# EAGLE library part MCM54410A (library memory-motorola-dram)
MEMORY

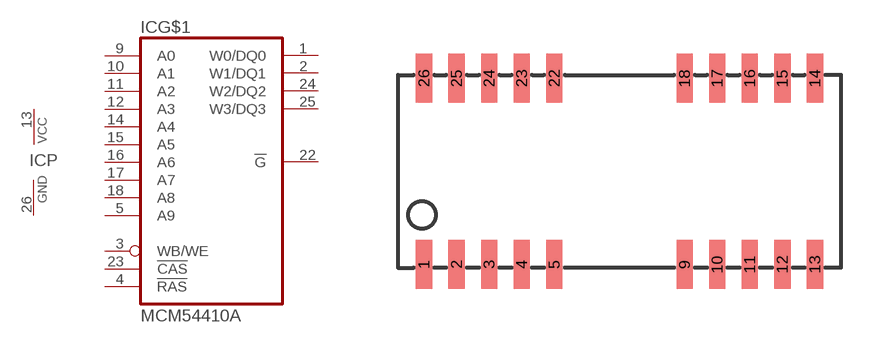
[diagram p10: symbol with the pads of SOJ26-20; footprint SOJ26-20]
Designator prefix IC; gates G$1=CM54410A P=PWRN

## MCM54410A (OC_FARNELL: unknown; OC_NEWARK: unknown)  [SOJ26-20]
1  G$1:W0/DQ0
2  G$1:W1/DQ1
3  G$1:WB/WE  in
4  G$1:!RAS  in
5  G$1:A9  in
9  G$1:A0  in
10  G$1:A1  in
11  G$1:A2  in
12  G$1:A3  in
13  P:VCC  pwr
14  G$1:A4  in
15  G$1:A5  in
16  G$1:A6  in
17  G$1:A7  in
18  G$1:A8  in
22  G$1:!G  in
23  G$1:!CAS  in
24  G$1:W2/DQ2
25  G$1:W3/DQ3
26  P:GND  pwr

## Footprint SOJ26-20 (pad centres in mm)
Small Outline J-Bend
smd 0.635 x 1.905: 1 -7.62,-3.632; 2 -6.35,-3.632; 3 -5.08,-3.632; 4 -3.81,-3.632; 5 -2.54,-3.632; 9 2.54,-3.632; 10 3.81,-3.632; 11 5.08,-3.632; 12 6.35,-3.632; 13 7.62,-3.632; 14 7.62,3.632; 15 6.35,3.632; 16 5.08,3.632; 17 3.81,3.632; 18 2.54,3.632; 22 -2.54,3.632; 23 -3.81,3.632; 24 -5.08,3.632; 25 -6.35,3.632; 26 -7.62,3.632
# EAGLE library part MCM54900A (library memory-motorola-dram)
MEMORY

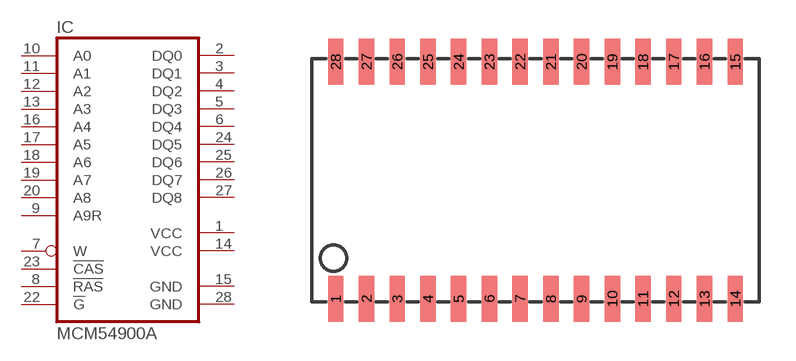
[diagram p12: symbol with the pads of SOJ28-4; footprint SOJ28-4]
Designator prefix IC

## MCM54900A (OC_FARNELL: unknown; OC_NEWARK: unknown)  [SOJ28-4]
1  VCC  pwr
2  DQ0
3  DQ1
4  DQ2
5  DQ3
6  DQ4
7  W  in
8  !RAS  in
9  A9R  in
10  A0  in
11  A1  in
12  A2  in
13  A3  in
14  VCC  pwr
15  GND  pwr
16  A4  in
17  A5  in
18  A6  in
19  A7  in
20  A8  in
22  !G  in
23  !CAS  in
24  DQ5
25  DQ6
26  DQ7
27  DQ8
28  GND  pwr

## Footprint SOJ28-4 (pad centres in mm)
Small Outline J-Bend
smd 0.635 x 1.905: 1 -8.255,-4.902; 2 -6.985,-4.902; 3 -5.715,-4.902; 4 -4.445,-4.902; 5 -3.175,-4.902; 6 -1.905,-4.902; 7 -0.635,-4.902; 8 0.635,-4.902; 9 1.905,-4.902; 10 3.175,-4.902; 11 4.445,-4.902; 12 5.715,-4.902; 13 6.985,-4.902; 14 8.255,-4.902; 15 8.255,4.902; 16 6.985,4.902; 17 5.715,4.902; 18 4.445,4.902; 19 3.175,4.902; 20 1.905,4.902; 21 0.635,4.902; 22 -0.635,4.902; 23 -1.905,4.902; 24 -3.175,4.902; 25 -4.445,4.902; 26 -5.715,4.902; 27 -6.985,4.902; 28 -8.255,4.902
